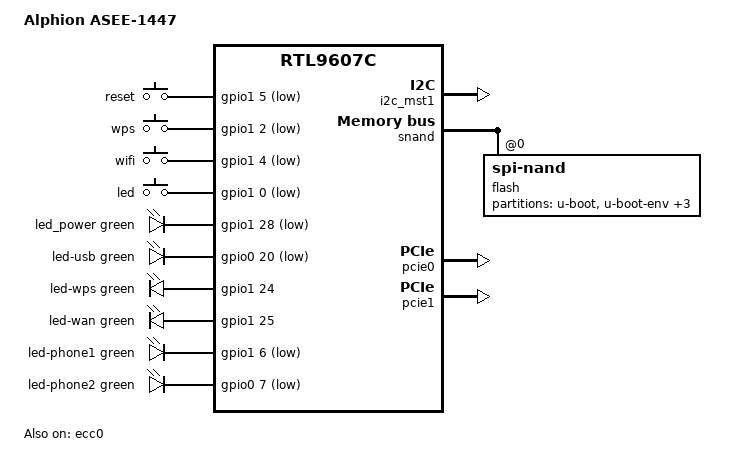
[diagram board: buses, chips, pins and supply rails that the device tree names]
// SPDX-License-Identifier: GPL-2.0-or-later OR MIT

/dts-v1/;

#include "rtl9607c-va.dtsi"
#include <dt-bindings/input/input.h>
#include <dt-bindings/leds/common.h>

/ {
	compatible = "alphion,asee-1447", "realtek,rtl9607c-soc";

	model = "Alphion ASEE-1447";

	chosen {
		bootargs = "earlycon ubi.block=0,ubi_r1 root=/dev/ubiblock0_4";
	};

	aliases {
		led-boot = &led_power;
		led-failsafe = &led_power;
		led-running = &led_power;
		led-upgrade = &led_power;
	};

	keys {
		compatible = "gpio-keys";

		pinctrl-0 = <&pinmux_gpio_buttons>;
		pinctrl-names = "default";

		reset {
			label = "reset";
			gpios = <&gpio1 5 GPIO_ACTIVE_LOW>;
			linux,code = <KEY_RESTART>;
		};

		wps {
			label = "wps";
			gpios = <&gpio1 2 GPIO_ACTIVE_LOW>;
			linux,code = <KEY_WPS_BUTTON>;
		};

		wifi {
			label = "wifi";
			gpios = <&gpio1 4 GPIO_ACTIVE_LOW>;
			linux,code = <KEY_RFKILL>;
		};

		led-toggle {
			label = "led";
			gpios = <&gpio1 0 GPIO_ACTIVE_LOW>;
			linux,code = <KEY_LIGHTS_TOGGLE>;
		};
	};

	leds {
		compatible = "gpio-leds";

		pinctrl-0 = <&pinmux_gpio0_leds>, <&pinmux_gpio1_leds>;
		pinctrl-names = "default";

		led_power: power {
			color = <LED_COLOR_ID_GREEN>;
			function = LED_FUNCTION_POWER;
			gpios = <&gpio1 28 GPIO_ACTIVE_LOW>;
		};

		led-usb {
			color = <LED_COLOR_ID_GREEN>;
			function = LED_FUNCTION_USB;
			gpios = <&gpio0 20 GPIO_ACTIVE_LOW>;
		};

		led-wps {
			color = <LED_COLOR_ID_GREEN>;
			function = LED_FUNCTION_WPS;
			gpios = <&gpio1 24 GPIO_ACTIVE_HIGH>;
		};

		led-wan {
			color = <LED_COLOR_ID_GREEN>;
			function = LED_FUNCTION_WAN;
			gpios = <&gpio1 25 GPIO_ACTIVE_HIGH>;
		};

		led-phone1 {
			color = <LED_COLOR_ID_GREEN>;
			function = "phone";
			function-enumerator = <1>;
			gpios = <&gpio1 6 GPIO_ACTIVE_LOW>;
		};

		led-phone2 {
			color = <LED_COLOR_ID_GREEN>;
			function = "phone";
			function-enumerator = <2>;
			gpios = <&gpio0 7 GPIO_ACTIVE_LOW>;
		};
	};
};

&pinmux {
	pinmux_gpio_buttons: gpio-buttons {
		pinctrl-single,bits = <0x4 0x35 0x35>;
	};

	pinmux_gpio0_leds: gpio0-leds {
		pinctrl-single,bits = <0x0 0x100080 0x100080>;
	};

	pinmux_gpio1_leds: gpio1-leds {
		pinctrl-single,bits = <0x4 0x13000040 0x13000040>;
	};
};

&i2c_mst1 {
	status = "okay";

	/* i2c of the BOSA (EEPROM at 0x50/0x51) */
	i2c0: i2c@0 {
		reg = <0>;
	};
};

&ecc0 {
	status = "okay";
};

&snand {
	status = "okay";

	flash@0 {
		compatible = "spi-nand";
		reg = <0>;

		nand-ecc-engine = <&ecc0>;
		nand-ecc-strength = <6>;
		nand-ecc-step-size = <512>;
		nand-ecc-algo = "bch";
		nand-ecc-placement = "oob";

		partitions {
			compatible = "fixed-partitions";
			#address-cells = <1>;
			#size-cells = <1>;

			partition@0 {
				label = "u-boot";
				reg = <0x0 0xc0000>;
				read-only;
			};

			partition@c0000 {
				compatible = "u-boot,env-redundant-count";
				label = "u-boot-env";
				reg = <0xc0000 0x20000>;
			};

			partition@e0000 {
				compatible = "u-boot,env-redundant-count";
				label = "u-boot-env2";
				reg = <0xe0000 0x20000>;
			};

			partition@100000 {
				label = "static_conf";
				reg = <0x100000 0x40000>;
				read-only;
			};

			partition@140000 {
				label = "ubi";
				reg = <0x140000 0xf9c0000>;
			};
		};
	};
};

&mdio_ctrl {
	PHY_C22(0, 0)
	PHY_C22(1, 1)
	PHY_C22(2, 2)
	PHY_C22(3, 3)
};

&switch0 {
	ethernet-ports {
		SWITCH_PORT(0, 1, internal)
		SWITCH_PORT(1, 2, internal)
		SWITCH_PORT(2, 3, internal)
		SWITCH_PORT(3, 4, internal)
	};
};

&pcie0 {
	status = "okay";
};

&pcie1 {
	status = "okay";
};
